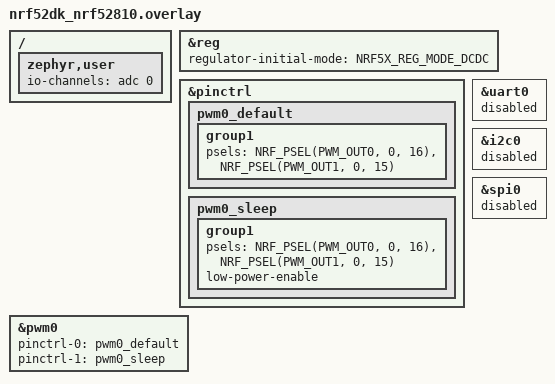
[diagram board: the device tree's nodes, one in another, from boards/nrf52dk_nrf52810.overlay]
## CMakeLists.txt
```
cmake_minimum_required(VERSION 3.20.0)
find_package(Zephyr REQUIRED HINTS $ENV{ZEPHYR_BASE})

project(nRF52810)

set(YUITAG_CORE_DIR ${CMAKE_CURRENT_SOURCE_DIR}/../../YuiTagCore)

target_include_directories(app PRIVATE
    ${CMAKE_CURRENT_SOURCE_DIR}/src
    ${YUITAG_CORE_DIR}/include
    ${YUITAG_CORE_DIR}/lib
)

target_sources(app PRIVATE
    src/main.c
    src/app.c
    src/yuitag_platform.c
    src/yuitag_buzzer.c
    src/yuitag_ble.c
    src/yuitag_findmy.c
    ${YUITAG_CORE_DIR}/src/yuitag_device.c
    ${YUITAG_CORE_DIR}/src/yuitag_crypto_common.c
    ${YUITAG_CORE_DIR}/src/yuitag_adv.c
    ${YUITAG_CORE_DIR}/src/yuitag_beep.c
    ${YUITAG_CORE_DIR}/lib/tiny_aes.c
    ${YUITAG_CORE_DIR}/lib/sha256.c
)

target_compile_definitions(app PRIVATE IS_SPARKS)
```

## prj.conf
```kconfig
# ============================================================
# YuiTag nRF52810 精简版项目编译配置
# 特性: 支持固定公钥组 FindMy / 裁剪 ECDH 软计算 / 裁剪 OTA / 裁剪 RTT 日志 / 无 MCUboot
# ============================================================

# --- 系统内核与时钟 ---
CONFIG_SYS_CLOCK_TICKS_PER_SEC=1000
CONFIG_MAIN_STACK_SIZE=1536
CONFIG_HEAP_MEM_POOL_SIZE=1024
CONFIG_SYSTEM_WORKQUEUE_STACK_SIZE=1024
CONFIG_ISR_STACK_SIZE=1024
CONFIG_PM_DEVICE=y

# --- 蓝牙协议栈 (从机从设备模式) ---
CONFIG_BT=y
CONFIG_BT_PERIPHERAL=y
CONFIG_BT_RX_STACK_SIZE=1280
CONFIG_BT_HCI_TX_STACK_SIZE=768
CONFIG_BT_DEVICE_NAME_DYNAMIC=y
CONFIG_BT_DEVICE_NAME_MAX=24
CONFIG_BT_MAX_CONN=1
CONFIG_BT_EXT_ADV=y
CONFIG_BT_EXT_ADV_MAX_ADV_SET=2
CONFIG_BT_ID_MAX=2
CONFIG_BT_BUF_ACL_RX_SIZE=64
CONFIG_BT_BUF_ACL_TX_SIZE=64
CONFIG_BT_L2CAP_TX_MTU=64
CONFIG_BT_ATT_PREPARE_COUNT=1
CONFIG_BT_BUF_EVT_RX_COUNT=6
CONFIG_BT_ASSERT=n

# 优选连接参数 (由应用层 yuitag_ble_try_conn_param_update 延迟 15 秒温和更新，禁用协议栈自动无条件降速)
CONFIG_BT_GAP_AUTO_UPDATE_CONN_PARAMS=n
CONFIG_BT_PERIPHERAL_PREF_MIN_INT=48
CONFIG_BT_PERIPHERAL_PREF_MAX_INT=72
CONFIG_BT_PERIPHERAL_PREF_LATENCY=0
CONFIG_BT_PERIPHERAL_PREF_TIMEOUT=400

# --- 硬件真随机数熵源 (用于配对密钥生成) ---
CONFIG_ENTROPY_GENERATOR=y
CONFIG_ENTROPY_NRF5_RNG=y

# --- NVS 持久化存储 ---
CONFIG_NVS=y
CONFIG_NVS_LOOKUP_CACHE=y
CONFIG_FLASH=y
CONFIG_FLASH_MAP=y
CONFIG_FLASH_PAGE_LAYOUT=y
CONFIG_MPU_ALLOW_FLASH_WRITE=y

# --- PWM 驱动 (压电蜂鸣器) ---
CONFIG_PWM=y

# --- SAADC 驱动 (电源轨 VDD 电池电量采集) ---
CONFIG_ADC=y

# --- 禁用控制台与 RTT 串口日志 (极度优化待机功耗与固件体积) ---
CONFIG_CONSOLE=n
CONFIG_USE_SEGGER_RTT=n
CONFIG_RTT_CONSOLE=n
CONFIG_UART_CONSOLE=n

# --- 射频发射功率 (最大 +4 dBm，保证最佳通信距离) ---
CONFIG_BT_CTLR_TX_PWR_ANTENNA=4
CONFIG_BT_HCI_VS=y
CONFIG_BT_CTLR_TX_PWR_DYNAMIC_CONTROL=y
```

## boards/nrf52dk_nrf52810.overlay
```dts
/*
 * YuiTag nRF52810 板级设备树 Overlay 配置:
 * 1. PWM0 驱动压电蜂鸣器差分互补输出: P0.16 (OUT0 正向, BUZZER+) / P0.15 (OUT1 反向, BUZZER-)。
 * 2. SAADC 通道 0 采样内部 VDD 电源轨，用于电池电量预估。
 * 3. 启用 SoC 内部 DC/DC 转换器降低运行功耗。
 * 4. 禁用未使用的 UART0 / I2C0 / SPI0 外设以节省静态电流。
 */

#include <zephyr/dt-bindings/regulator/nrf5x.h>

/ {
	zephyr,user {
		io-channels = <&adc 0>;
	};
};

/* 启用 SoC 内部 DC/DC 降压转换器 */
&reg {
	regulator-initial-mode = <NRF5X_REG_MODE_DCDC>;
};

&pinctrl {
	pwm0_default: pwm0_default {
		group1 {
			psels = <NRF_PSEL(PWM_OUT0, 0, 16)>,
				<NRF_PSEL(PWM_OUT1, 0, 15)>;
		};
	};

	pwm0_sleep: pwm0_sleep {
		group1 {
			psels = <NRF_PSEL(PWM_OUT0, 0, 16)>,
				<NRF_PSEL(PWM_OUT1, 0, 15)>;
			low-power-enable;
		};
	};
};

&pwm0 {
	status = "okay";
	pinctrl-0 = <&pwm0_default>;
	pinctrl-1 = <&pwm0_sleep>;
	pinctrl-names = "default", "sleep";
};

&uart0 {
	status = "disabled";
};

&i2c0 {
	status = "disabled";
};

&spi0 {
	status = "disabled";
};
```

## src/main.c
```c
// ============================================================
// YuiTag 固件程序入口与启动时序
// 硬件平台: Nordic nRF52810 / nRF Connect SDK (Zephyr)
// ============================================================

#include <zephyr/kernel.h>
#include <zephyr/bluetooth/bluetooth.h>

#include "yuitag_config.h"
#include "yuitag_platform.h"
#include "yuitag_crypto.h"
#include "yuitag_device.h"
#include "yuitag_buzzer_types.h"
#include "yuitag_ble.h"
#include "yuitag_findmy.h"
#include "app.h"

static YuiTagDevice g_dev;

// 蓝牙协议栈异步初始化就绪回调
static void bt_ready(int err)
{
    if (err) {
        platform_log("[BT] enable failed: %d", err);
        return;
    }

    platform_log("[BT] Ready");

    // 1. 获取芯片硬件 MAC 地址并初始化设备状态机与配置
    uint8_t mac[6];
    platform_get_mac(mac);
    yuitag_device_init(&g_dev, mac);

    // 2. 检测短时连续快速上电 (防抖窗口内达 5 次触发恢复出厂)
    bool resetTriggered = yuitag_device_power_cycle_check(&g_dev);

    // 3. 正常开机蜂鸣提示音 (若触发出厂复位则跳过，避免覆盖复位提示音)
    if (!resetTriggered) {
        yuitag_beep_startup();
    }

    // 4. 同步设备名称至 BLE 协议栈及 DIS 信息服务
    yuitag_ble_set_device_name(g_dev.deviceName);
    yuitag_ble_update_dis_values(&g_dev);
    yuitag_ble_update_param_value(&g_dev);

    // 5. 启动 BLE 广播 (未绑定时慢广播，已绑定时常态广播)
    yuitag_ble_update_advertising(&g_dev, true);

    // 6. 初始化 Find My 模块并在使能时启动轮换广播
    yuitag_findmy_init();
    yuitag_ble_update_param_value(&g_dev);
    if (g_dev.findmyEnabled) {
        if (!yuitag_findmy_enable()) {
            g_dev.findmyEnabled = false;
            platform_log("[FINDMY] Enable failed at boot, reverting flag");
            yuitag_ble_update_param_value(&g_dev);
        } else {
            yuitag_findmy_update_battery(g_dev.batteryLevel);
        }
    }

    // 7. 标记系统初始化完成，使能异步工作队列事件调度
    app_mark_initialized();
    platform_log("[BOOT] YuiTag initialized");
}

int main(void)
{
    // 基础硬件平台与外设初始化 (NVS 存储挂载、PWM 蜂鸣器引脚)
    platform_init();

    // 软件加密工具层初始化
    yuitag_crypto_init();

    // 异步工作队列调度器与定时器初始化
    app_init(&g_dev);

    // 注册 BLE 协议栈连接与 GATT 回调
    yuitag_ble_init(&g_dev);

    // 异步启动 Zephyr 蓝牙协议栈
    int err = bt_enable(bt_ready);
    if (err) {
        platform_log("[BT] bt_enable failed: %d", err);
    }

    // 主线程永久休眠，完全由中断与系统工作队列驱动，达到最大程度低功耗
    while (1) {
        k_sleep(K_FOREVER);
    }
    return 0;
}
```

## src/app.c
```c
// ============================================================
// YuiTag 业务事件调度中枢 (工作队列异步处理)
// 设计目的: 将耗时的 Flash 擦写 (NVS)、广播重启等操作移出蓝牙回调
//          与中断上下文，统一在 Zephyr 系统工作队列 (System Workqueue) 中安全消费。
// ============================================================

#include "app.h"
#include "yuitag_platform.h"
#include "yuitag_ble.h"

#include <zephyr/kernel.h>

static YuiTagDevice *g_dev;
static bool g_initialized = false;

static struct k_work s_process_work;
static struct k_timer s_periodic_timer;

static void process_action_handler(struct k_work *work);

// 核心业务异步消费处理函数 (调用 YuiTagCore 统一事件处理中枢)
static void process_action_handler(struct k_work *work)
{
    (void)work;
    if (!g_initialized || !g_dev) {
        return;
    }

    yuitag_device_process_events(g_dev);
}

// 系统周期定时器中断回调 (定期向工作队列提交消费任务)
static void periodic_timer_handler(struct k_timer *timer)
{
    (void)timer;
    app_proceed();
}

void app_init(YuiTagDevice *dev)
{
    g_dev = dev;

    k_work_init(&s_process_work, process_action_handler);
    k_timer_init(&s_periodic_timer, periodic_timer_handler, NULL);
    k_timer_start(&s_periodic_timer,
                  K_SECONDS(PERIODIC_CHECK_INTERVAL_MS / 1000),
                  K_SECONDS(PERIODIC_CHECK_INTERVAL_MS / 1000));
}

void app_proceed(void)
{
    k_work_submit(&s_process_work);
}

void app_mark_initialized(void)
{
    g_initialized = true;
    app_proceed();
}
```

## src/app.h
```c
#ifndef APP_H
#define APP_H

// ============================================================
// YuiTag 业务事件调度中枢 (工作队列异步处理)
// ============================================================

#include "yuitag_device.h"

// 初始化应用调度器 (绑定工作项与定时器)
void app_init(YuiTagDevice *dev);

// 提交工作队列项，触发异步事件消费处理
void app_proceed(void);

// 标记系统启动初始化完毕，使能事件消费
void app_mark_initialized(void);

#endif // APP_H
```

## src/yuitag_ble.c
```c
// ============================================================
// YuiTag BLE 协议栈与 GATT 通信层实现
// ============================================================

#include "yuitag_ble.h"
#include "yuitag_crypto.h"
#include "yuitag_platform.h"
#include "yuitag_adv.h"
#include "app.h"

#include <zephyr/bluetooth/bluetooth.h>
#include <zephyr/bluetooth/gatt.h>
#include <zephyr/bluetooth/uuid.h>
#include <zephyr/bluetooth/conn.h>
#include <zephyr/sys/byteorder.h>
#include <zephyr/sys/util.h>
#include <zephyr/kernel.h>

#include <string.h>

// 128 位完整 UUID 声明
#define YUITAG_UUID_SVC   BT_UUID_DECLARE_128(BT_UUID_128_ENCODE(0x722aaa00, 0x8a74, 0x432f, 0x9055, 0x7ed8a5584a11))
#define YUITAG_UUID_BIND  BT_UUID_DECLARE_128(BT_UUID_128_ENCODE(0x722aaa42, 0x8a74, 0x432f, 0x9055, 0x7ed8a5584a11))
#define YUITAG_UUID_CMD   BT_UUID_DECLARE_128(BT_UUID_128_ENCODE(0x722aaa43, 0x8a74, 0x432f, 0x9055, 0x7ed8a5584a11))
#define YUITAG_UUID_PARAM BT_UUID_DECLARE_128(BT_UUID_128_ENCODE(0x722aaa46, 0x8a74, 0x432f, 0x9055, 0x7ed8a5584a11))

static YuiTagDevice *g_dev;
static struct bt_conn *g_conn;
static bool g_connected = false;
static bool g_cccd_bind = false;
static bool g_cccd_cmd  = false;
static bool g_cccd_param = false;
static bool g_adv_failed = false;

static uint32_t g_conn_start_ms = 0;
static bool g_conn_param_updated = false;
static struct k_work_delayable s_conn_param_work;
static void conn_param_work_handler(struct k_work *work);

static struct k_work_delayable s_adv_refresh_work;
static void adv_refresh_work_handler(struct k_work *work)
{
    (void)work;
    if (g_dev) {
        yuitag_ble_update_advertising(g_dev, true);
        app_proceed();
    }
}

// CCCD 客户端通知特性描述符状态监听
static void ccc_bind_changed(const struct bt_gatt_attr *attr, uint16_t value)
{
    (void)attr;
    g_cccd_bind = (value == BT_GATT_CCC_NOTIFY);
    platform_log("[GATT] CCC bind notif=%d", g_cccd_bind);
}

static void ccc_cmd_changed(const struct bt_gatt_attr *attr, uint16_t value)
{
    (void)attr;
    g_cccd_cmd = (value == BT_GATT_CCC_NOTIFY);
    platform_log("[GATT] CCC cmd notif=%d", g_cccd_cmd);
}

static void ccc_param_changed(const struct bt_gatt_attr *attr, uint16_t value)
{
    (void)attr;
    g_cccd_param = (value == BT_GATT_CCC_NOTIFY);
    platform_log("[GATT] CCC param notif=%d", g_cccd_param);
}

// 根据特征 UUID 向客户端发送 GATT Notify 通知
static void notify_by_uuid(const struct bt_uuid *uuid,
                           const uint8_t *data, size_t len)
{
    if (!g_conn) {
        return;
    }

    bool ccc_enabled;
    if (!bt_uuid_cmp(uuid, YUITAG_UUID_BIND)) {
        ccc_enabled = g_cccd_bind;
    } else if (!bt_uuid_cmp(uuid, YUITAG_UUID_CMD)) {
        ccc_enabled = g_cccd_cmd;
    } else if (!bt_uuid_cmp(uuid, YUITAG_UUID_PARAM)) {
        ccc_enabled = g_cccd_param;
    } else {
        return;
    }

    if (!ccc_enabled) {
        return;
    }

    uint16_t mtu = bt_gatt_get_mtu(g_conn);
    if (len > (size_t)(mtu - 3)) {
        return;
    }

    struct bt_gatt_notify_params params = {
        .uuid = uuid,
        .attr = NULL,
        .data = data,
        .len = (uint16_t)len,
        .func = NULL,
        .user_data = NULL,
    };
    bt_gatt_notify_cb(g_conn, &params);
}

// 根据通道向客户端发送 GATT Notify 通知
static void send_notify_by_ch(yuitag_notify_ch_t ch, const uint8_t *data, size_t len)
{
    switch (ch) {
    case YUITAG_NOTIFY_BIND:
        notify_by_uuid(YUITAG_UUID_BIND, data, len);
        break;
    case YUITAG_NOTIFY_CMD:
        notify_by_uuid(YUITAG_UUID_CMD, data, len);
        break;
    case YUITAG_NOTIFY_PARAM:
        notify_by_uuid(YUITAG_UUID_PARAM, data, len);
        break;
    default:
        break;
    }
}

// 设备信息服务 (DIS) 静态字符串读取
static ssize_t read_dis_string(struct bt_conn *conn,
                               const struct bt_gatt_attr *attr,
                               void *buf, uint16_t len, uint16_t offset)
{
    const char *str = (const char *)attr->user_data;
    return bt_gatt_attr_read(conn, attr, buf, len, offset, str, strlen(str));
}

// 参数通道读取回调 (读取当前名称、广播间隔与状态)
static ssize_t read_param(struct bt_conn *conn,
                          const struct bt_gatt_attr *attr,
                          void *buf, uint16_t len, uint16_t offset)
{
    uint8_t paramBuf[PARAM_DECRYPT_BUF_MAX_LEN];
    size_t paramLen = yuitag_device_param_read(g_dev, paramBuf, sizeof(paramBuf));
    if (paramLen == 0) {
        return BT_GATT_ERR(BT_ATT_ERR_UNLIKELY);
    }
    return bt_gatt_attr_read(conn, attr, buf, len, offset, paramBuf, paramLen);
}

// 绑定特征写入回调 (触发设备端生成随机 AES 密钥并通过 Notify 发送给客户端)
static ssize_t write_bind(struct bt_conn *conn, const struct bt_gatt_attr *attr,
                          const void *buf, uint16_t len, uint16_t offset, uint8_t flags)
{
    (void)conn; (void)attr; (void)offset; (void)flags; (void)buf; (void)len;

    if (g_dev->isBound) {
        platform_log("[BIND] Ignored: already bound");
        return len;
    }

    if (g_dev->waitingVerify) {
        platform_log("[BIND] Ignored: bind already in progress");
        return len;
    }

    uint8_t aesKey[AES_KEY_LEN];
    if (!yuitag_device_bind_generate_key(g_dev, aesKey)) {
        uint8_t fail = STATUS_FAILED;
        notify_by_uuid(YUITAG_UUID_BIND, &fail, 1);
        g_dev->pendingBindAbort = true;
        app_proceed();
        return len;
    }

    notify_by_uuid(YUITAG_UUID_BIND, aesKey, AES_KEY_LEN);
    platform_log("[BIND] Sent AES key (%d bytes)", AES_KEY_LEN);
    return len;
}

// 指令通道写入回调 (处理绑定验证包及各类加密业务指令)
static ssize_t write_cmd(struct bt_conn *conn, const struct bt_gatt_attr *attr,
                         const void *buf, uint16_t len, uint16_t offset, uint8_t flags)
{
    (void)conn; (void)attr; (void)offset; (void)flags;

    yuitag_response_t resp = {0};
    yuitag_device_handle_cmd_write(g_dev, buf, len, &resp);

    if (resp.channel != YUITAG_NOTIFY_NONE) {
        send_notify_by_ch(resp.channel, resp.data, resp.len);
    }

    if (g_dev->pendingConnParamReset) {
        g_dev->pendingConnParamReset = false;
        yuitag_ble_update_dis_values(g_dev);
        g_conn_param_updated = false;
        k_work_reschedule(&s_conn_param_work, K_MSEC(CONN_PARAM_DELAY_MS));
    }

    if (g_dev->pendingUnbindClear || g_dev->pendingAdvRefresh || g_dev->pendingBindAbort) {
        app_proceed();
    }

    return len;
}

// 参数通道写入回调 (处理加密的设备名称与广播间隔修改)
static ssize_t write_param(struct bt_conn *conn, const struct bt_gatt_attr *attr,
                           const void *buf, uint16_t len, uint16_t offset, uint8_t flags)
{
    (void)conn; (void)attr; (void)offset; (void)flags;

    yuitag_response_t resp = {0};
    yuitag_device_handle_param_write(g_dev, buf, len, &resp);

    if (resp.channel != YUITAG_NOTIFY_NONE) {
        send_notify_by_ch(resp.channel, resp.data, resp.len);
    }

    if (g_dev->pendingParamSave || g_dev->pendingAdvRefresh) {
        app_proceed();
    }
    yuitag_ble_update_param_value(g_dev);

    return len;
}

static ssize_t read_serial(struct bt_conn *conn,
                           const struct bt_gatt_attr *attr,
                           void *buf, uint16_t len, uint16_t offset);

static ssize_t read_system_id(struct bt_conn *conn,
                              const struct bt_gatt_attr *attr,
                              void *buf, uint16_t len, uint16_t offset);

// ============================================================
// GATT 服务结构定义
// ============================================================

// 标准设备信息服务 (DIS: 0x180A)
BT_GATT_SERVICE_DEFINE(dis_svc,
    BT_GATT_PRIMARY_SERVICE(BT_UUID_DIS),
    BT_GATT_CHARACTERISTIC(BT_UUID_DECLARE_16(0x2A29),
        BT_GATT_CHRC_READ, BT_GATT_PERM_READ, read_dis_string, NULL, (void *)MANUFACTURER),
    BT_GATT_CHARACTERISTIC(BT_UUID_DECLARE_16(0x2A24),
        BT_GATT_CHRC_READ, BT_GATT_PERM_READ, read_dis_string, NULL, (void *)MODEL_NUMBER),
    BT_GATT_CHARACTERISTIC(BT_UUID_DECLARE_16(0x2A25),
        BT_GATT_CHRC_READ, BT_GATT_PERM_READ, read_serial, NULL, NULL),
    BT_GATT_CHARACTERISTIC(BT_UUID_DECLARE_16(0x2A23),
        BT_GATT_CHRC_READ, BT_GATT_PERM_READ, read_system_id, NULL, NULL),
    BT_GATT_CHARACTERISTIC(BT_UUID_DECLARE_16(0x2A27),
        BT_GATT_CHRC_READ, BT_GATT_PERM_READ, read_dis_string, NULL, (void *)HW_VERSION),
    BT_GATT_CHARACTERISTIC(BT_UUID_DECLARE_16(0x2A26),
        BT_GATT_CHRC_READ, BT_GATT_PERM_READ, read_dis_string, NULL, (void *)FW_VERSION),
    BT_GATT_CHARACTERISTIC(BT_UUID_DECLARE_16(0x2A28),
        BT_GATT_CHRC_READ, BT_GATT_PERM_READ, read_dis_string, NULL, (void *)YUITAG_CORE_VERSION),
);

// YuiTag 核心服务 (Core Service: 0xAA00)
BT_GATT_SERVICE_DEFINE(yuitag_core_svc,
    BT_GATT_PRIMARY_SERVICE(YUITAG_UUID_SVC),

    // 绑定握手特征 (0xAA42)
    BT_GATT_CHARACTERISTIC(YUITAG_UUID_BIND,
        BT_GATT_CHRC_WRITE | BT_GATT_CHRC_NOTIFY,
        BT_GATT_PERM_WRITE, NULL, write_bind, NULL),
    BT_GATT_CCC(ccc_bind_changed, BT_GATT_PERM_READ | BT_GATT_PERM_WRITE),

    // 控制指令通道特征 (0xAA43)
    BT_GATT_CHARACTERISTIC(YUITAG_UUID_CMD,
        BT_GATT_CHRC_WRITE | BT_GATT_CHRC_NOTIFY,
        BT_GATT_PERM_WRITE, NULL, write_cmd, NULL),
    BT_GATT_CCC(ccc_cmd_changed, BT_GATT_PERM_READ | BT_GATT_PERM_WRITE),

    // 参数配置通道特征 (0xAA46)
    BT_GATT_CHARACTERISTIC(YUITAG_UUID_PARAM,
        BT_GATT_CHRC_READ | BT_GATT_CHRC_WRITE | BT_GATT_CHRC_NOTIFY,
        BT_GATT_PERM_READ | BT_GATT_PERM_WRITE, read_param, write_param, NULL),
    BT_GATT_CCC(ccc_param_changed, BT_GATT_PERM_READ | BT_GATT_PERM_WRITE),
);

// 读取序列号特征
static ssize_t read_serial(struct bt_conn *conn,
                           const struct bt_gatt_attr *attr,
                           void *buf, uint16_t len, uint16_t offset)
{
    if (!g_dev) {
        return BT_GATT_ERR(BT_ATT_ERR_UNLIKELY);
    }
    return bt_gatt_attr_read(conn, attr, buf, len, offset,
                             g_dev->serial, strlen(g_dev->serial));
}

// 读取系统 ID 特征 (由 MAC 转换为 EUI-64 格式, 构造逻辑在 YuiTagCore)
static ssize_t read_system_id(struct bt_conn *conn,
                              const struct bt_gatt_attr *attr,
                              void *buf, uint16_t len, uint16_t offset)
{
    uint8_t mac[6];
    uint8_t sid[8];

    platform_get_mac(mac);
    yuitag_crypto_make_system_id(mac, sid);

    return bt_gatt_attr_read(conn, attr, buf, len, offset, sid, sizeof(sid));
}

#include <zephyr/bluetooth/hci.h>
#if defined(CONFIG_BT_HCI_VS) || defined(CONFIG_BT_CTLR) || defined(CONFIG_BT_LL_SOFTDEVICE)
#include <zephyr/bluetooth/hci_vs.h>
#endif

static void set_adv_tx_power(int8_t power_dbm)
{
    int8_t valid_powers[] = { 4, 3, 0, -4, -8, -12, -16, -20, -40 };
    int8_t selected = -40;
    for (size_t i = 0; i < ARRAY_SIZE(valid_powers); i++) {
        if (power_dbm >= valid_powers[i]) {
            selected = valid_powers[i];
            break;
        }
    }

#if defined(BT_HCI_OP_VS_WRITE_TX_POWER_LEVEL)
    struct bt_hci_cp_vs_write_tx_power_level *cp;
    struct net_buf *buf, *rsp = NULL;

    buf = bt_hci_cmd_alloc(K_FOREVER);
    if (buf) {
        cp = net_buf_add(buf, sizeof(*cp));
        cp->handle_type = BT_HCI_VS_LL_HANDLE_TYPE_ADV;
        cp->handle = sys_cpu_to_le16(0);
        cp->tx_power_level = selected;

        int err = bt_hci_cmd_send_sync(BT_HCI_OP_VS_WRITE_TX_POWER_LEVEL, buf, &rsp);
        if (err) {
            platform_log("[ADV] Set TX power (%d dBm) failed: %d", selected, err);
        } else {
            int8_t actual = selected;
            if (rsp && rsp->len >= sizeof(struct bt_hci_rp_vs_write_tx_power_level)) {
                struct bt_hci_rp_vs_write_tx_power_level *rp = (void *)rsp->data;
                actual = rp->selected_tx_power;
            }
            platform_log("[ADV] Set TX power: %d dBm (actual: %d dBm)", selected, actual);
        }
        if (rsp) {
            net_buf_unref(rsp);
        }
    }
#else
    ARG_UNUSED(selected);
#endif
}

// 组装广播包与扫描响应包并启动广播 (字段布局由 YuiTagCore yuitag_adv 统一构造)
static void start_advertising(YuiTagDevice *dev, bool connectable)
{
    // 主广播包字段段 (flags + 厂商数据 + [绑定后]电量 + [debug]诊断)
    uint8_t adStorage[32];
    yuitag_adv_seg_t adSegs[4];
    size_t adSegCount = yuitag_adv_build(dev, adSegs, ARRAY_SIZE(adSegs),
                                         adStorage, sizeof(adStorage));
    if (adSegCount == 0) {
        platform_log("[ADV] Failed to build adv data");
        g_adv_failed = true;
        return;
    }

    struct bt_data ad[4];
    size_t adLen = 0;
    for (size_t i = 0; i < adSegCount && adLen < ARRAY_SIZE(ad); i++) {
        ad[adLen].type = adSegs[i].type;
        ad[adLen].data_len = adSegs[i].len;
        ad[adLen].data = adSegs[i].data;
        adLen++;
    }

    // 扫描响应包中包含完整设备名称
    uint8_t sdStorage[DEVICE_NAME_MAX_LEN + 1];
    yuitag_adv_seg_t sdSegs[1];
    size_t sdSegCount = yuitag_adv_build_scan_rsp(dev, sdSegs, ARRAY_SIZE(sdSegs),
                                                  sdStorage, sizeof(sdStorage));

    struct bt_data sd[1];
    size_t sdLen = 0;
    if (sdSegCount == 1) {
        sd[0].type = sdSegs[0].type;
        sd[0].data_len = sdSegs[0].len;
        sd[0].data = sdSegs[0].data;
        sdLen = 1;
    }

    // 毫秒折算为 0.625ms 广播单位
    uint32_t units = ((uint32_t)dev->advInterval * 8U) / 5U;
    uint32_t opt = BT_LE_ADV_OPT_USE_IDENTITY;
    opt |= connectable ? BT_LE_ADV_OPT_CONN : BT_LE_ADV_OPT_SCANNABLE;
    struct bt_le_adv_param param = BT_LE_ADV_PARAM_INIT(opt, units, units, NULL);

    int err = bt_le_adv_start(&param, ad, adLen, sd, sdLen);
    if (err) {
        platform_log("[ADV] Start failed: %d", err);
        g_adv_failed = true;
        return;
    }

    set_adv_tx_power(dev->txPower);

    g_adv_failed = false;
    platform_log("[ADV] Mode=%s connectable=%d interval=%dms txPower=%d",
                 dev->isBound ? "Normal" : "Initial", connectable, dev->advInterval, dev->txPower);
}

void yuitag_ble_update_advertising(YuiTagDevice *dev, bool rebuild_data)
{
    (void)rebuild_data;
    bt_le_adv_stop();
    start_advertising(dev, !g_connected);
}

bool yuitag_ble_adv_failed(void)
{
    return g_adv_failed;
}

void yuitag_ble_disconnect(void)
{
    if (g_conn) {
        bt_conn_disconnect(g_conn, BT_HCI_ERR_REMOTE_USER_TERM_CONN);
    }
}

bool yuitag_ble_is_connected(void)
{
    return g_connected;
}

void yuitag_ble_update_param_value(YuiTagDevice *dev)
{
    (void)dev;
}

void yuitag_ble_update_dis_values(YuiTagDevice *dev)
{
    bt_set_name(dev->deviceName);
}

void yuitag_ble_set_device_name(const char *name)
{
    bt_set_name(name);
}

// 蓝牙连接建立回调
static void connected(struct bt_conn *conn, uint8_t err)
{
    if (err) {
        platform_log("[CONN] Connect failed: %u", err);
        return;
    }

    g_conn = bt_conn_ref(conn);
    g_connected = true;
    g_conn_start_ms = platform_millis();
    g_conn_param_updated = false;
    g_cccd_bind = g_cccd_cmd = g_cccd_param = false;

    yuitag_device_on_connected(g_dev);

    // 已绑定设备在连接建立 15.0 秒后尝试温和更新连接参数 (预留充裕窗口给服务发现与交互)
    if (g_dev && g_dev->isBound) {
        k_work_reschedule(&s_conn_param_work, K_MSEC(CONN_PARAM_DELAY_MS));
    }

    // 连接建立后延迟 30ms 重新配置不可连接广播，避开 BT_RX 协议栈清理竞态
    k_work_reschedule(&s_adv_refresh_work, K_MSEC(30));

    platform_log("[CONN] Connected");
}

// 蓝牙连接断开回调
static void disconnected(struct bt_conn *conn, uint8_t reason)
{
    (void)reason;
    k_work_cancel_delayable(&s_conn_param_work);

    if (g_conn) {
        bt_conn_unref(g_conn);
        g_conn = NULL;
    }
    g_connected = false;
    g_cccd_bind = g_cccd_cmd = g_cccd_param = false;

    yuitag_device_on_disconnected(g_dev);
    app_proceed();

    // 连接断开后延迟 30ms 恢复常态可连接广播，避开 BT_RX 协议栈清理竞态
    k_work_reschedule(&s_adv_refresh_work, K_MSEC(30));
    platform_log("[CONN] Disconnected (reason 0x%02x)", reason);
}

BT_CONN_CB_DEFINE(conn_callbacks) = {
    .connected = connected,
    .disconnected = disconnected,
};

static void conn_param_work_handler(struct k_work *work)
{
    (void)work;
    if (yuitag_device_is_keys_sync_active()) {
        platform_log("[CONN] Keys sync in progress, postpone conn param update");
        k_work_reschedule(&s_conn_param_work, K_SECONDS(5));
        return;
    }
    if (g_dev) {
        yuitag_ble_try_conn_param_update(g_dev);
    }
}

// 平衡功耗与响应的温和降速参数 (60ms~90ms, latency=0, timeout=4s)
void yuitag_ble_try_conn_param_update(YuiTagDevice *dev)
{
    if (!g_connected || g_conn_param_updated || !g_conn) {
        return;
    }
    if (!dev || !dev->isBound) {
        return;
    }
    if (platform_millis() - g_conn_start_ms < CONN_PARAM_DELAY_MS) {
        return;
    }
    if (yuitag_device_is_keys_sync_active()) {
        platform_log("[CONN] Keys sync in progress, postpone conn param update");
        k_work_reschedule(&s_conn_param_work, K_SECONDS(5));
        return;
    }

    struct bt_le_conn_param param = {
        .interval_min = CONN_PARAM_INTERVAL_MIN_UNITS,
        .interval_max = CONN_PARAM_INTERVAL_MAX_UNITS,
        .latency = CONN_PARAM_LATENCY,
        .timeout = CONN_PARAM_TIMEOUT_UNITS,
    };
    int err = bt_conn_le_param_update(g_conn, &param);
    if (err == 0) {
        g_conn_param_updated = true;
        platform_log("[CONN] Balanced param update requested: 60-90ms, lat=0, to=4s");
    } else {
        platform_log("[CONN] Param update failed: %d", err);
    }
}

void yuitag_ble_init(YuiTagDevice *dev)
{
    g_dev = dev;
    k_work_init_delayable(&s_conn_param_work, conn_param_work_handler);
    k_work_init_delayable(&s_adv_refresh_work, adv_refresh_work_handler);
}
```

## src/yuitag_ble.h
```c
#ifndef YUITAG_BLE_H
#define YUITAG_BLE_H

// ============================================================
// YuiTag BLE 协议栈与 GATT 通信层接口
// 硬件平台: Nordic nRF52810 / Zephyr Bluetooth Host
// 功能: 广播控制、GATT 核心服务与特征、连接参数协商、通知推送
// ============================================================

#include <zephyr/bluetooth/bluetooth.h>
#include "yuitag_device.h"
#include <stdbool.h>

// 初始化 BLE 驱动层上下文及连接参数更新工作项 (需在 bt_enable 前调用)
void yuitag_ble_init(YuiTagDevice *dev);

// 更新广播数据包内容并启动/重置广播
void yuitag_ble_update_advertising(YuiTagDevice *dev, bool rebuild_data);

// 主动断开当前 BLE 连接
void yuitag_ble_disconnect(void);

// 查询当前是否处于连接状态
bool yuitag_ble_is_connected(void);

// 查询广播启动是否发生错误
bool yuitag_ble_adv_failed(void);

// 触发参数特征与 DIS 服务相关值更新
void yuitag_ble_update_param_value(YuiTagDevice *dev);
void yuitag_ble_update_dis_values(YuiTagDevice *dev);
void yuitag_ble_set_device_name(const char *name);

// 尝试向主机发起连接参数更新请求 (遵循 Apple iOS 配件规范)
void yuitag_ble_try_conn_param_update(YuiTagDevice *dev);

#endif // YUITAG_BLE_H
```

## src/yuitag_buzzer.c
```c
// ============================================================
// YuiTag 蜂鸣器驱动层实现
// 硬件平台: Nordic nRF52810 / Zephyr PWM
// 驱动原理: 通道 0 与通道 1 互补差分输出 (180° 相位差)，获得倍增声压。
//          关闭时双通道均拉低至 0V，消除压电蜂鸣片直流偏置漏电。
// ============================================================

#include "yuitag_buzzer.h"

#include <zephyr/kernel.h>
#include <zephyr/device.h>
#include <zephyr/devicetree.h>
#include <zephyr/drivers/pwm.h>
#if defined(CONFIG_PM_DEVICE)
#include <zephyr/pm/device.h>
#endif
#include <hal/nrf_pwm.h>

#define BUZZER_NODE             DT_NODELABEL(pwm0)
#define BUZZER_DEV              DEVICE_DT_GET(BUZZER_NODE)
#define BUZZER_CH_P             0
#define BUZZER_CH_N             1

#define BUZZER_DEFAULT_FREQ     4000U       // 压电片共振主频 4kHz
#define BUZZER_DEFAULT_VOLUME   100U        // 默认满音量
#define BUZZER_TIMER_CLOCK_HZ   16000000U   // nRF52810 PWM 高频时钟 (16MHz)

static bool s_buzzer_on;
static uint32_t s_freq = BUZZER_DEFAULT_FREQ;
static uint8_t  s_volume_pct = BUZZER_DEFAULT_VOLUME;

static const buzzer_note_t *s_melody_notes;
static uint16_t             s_melody_count;
static uint16_t             s_melody_index;
static bool                 s_melody_repeat;
static bool                 s_melody_playing;
static buzzer_melody_done_cb s_melody_done_cb;

static struct k_work_delayable s_melody_work;

static void melody_step(struct k_work *work);
static void play_current_note(void);
static void timer_apply(void);

// 应用当前频率和音量到双路差分 PWM 输出
static void timer_apply(void)
{
    if (!device_is_ready(BUZZER_DEV)) {
        return;
    }

#if defined(CONFIG_PM_DEVICE)
    pm_device_action_run(BUZZER_DEV, PM_DEVICE_ACTION_RESUME);
#endif
    nrf_pwm_enable(NRF_PWM0);

    // 计算 PWM 周期计数值 (时钟频率 / 目标频率)
    uint32_t period = BUZZER_TIMER_CLOCK_HZ / s_freq;
    if (period < 2U) {
        period = 2U;
    }

    uint8_t vol = s_volume_pct;
    if (vol > 100U) {
        vol = 100U;
    }

    // 满音量对应 50% 占空比 (差分驱动下可达到最大振幅)
    uint32_t pulse = (period * vol) / 200U;
    if (pulse < 1U) {
        pulse = 1U;
    }
    if (pulse >= period) {
        pulse = period - 1U;
    }

    // 通道 0 正常极性，通道 1 反向极性 (形成 180° 差分信号)
    pwm_set_cycles(BUZZER_DEV, BUZZER_CH_P, period, pulse, PWM_POLARITY_NORMAL);
    pwm_set_cycles(BUZZER_DEV, BUZZER_CH_N, period, pulse, PWM_POLARITY_INVERTED);
}

void buzzer_init(void)
{
    s_buzzer_on    = false;
    s_volume_pct   = BUZZER_DEFAULT_VOLUME;
    s_freq         = BUZZER_DEFAULT_FREQ;
    s_melody_playing = false;

    if (device_is_ready(BUZZER_DEV)) {
        pwm_set_cycles(BUZZER_DEV, BUZZER_CH_P, 0, 0, PWM_POLARITY_NORMAL);
        pwm_set_cycles(BUZZER_DEV, BUZZER_CH_N, 0, 0, PWM_POLARITY_NORMAL);
#if defined(CONFIG_PM_DEVICE)
        pm_device_action_run(BUZZER_DEV, PM_DEVICE_ACTION_SUSPEND);
#endif
        nrf_pwm_disable(NRF_PWM0);
    }

    k_work_init_delayable(&s_melody_work, melody_step);
}

void buzzer_on(void)
{
    if (s_buzzer_on) {
        return;
    }
    timer_apply();
    s_buzzer_on = true;
}

void buzzer_off(void)
{
    if (!s_buzzer_on) {
        return;
    }
    if (device_is_ready(BUZZER_DEV)) {
        // 双通道均输出 0 脉宽正常极性 (拉低至 0V)，彻底消除直流偏置与静态漏电
        pwm_set_cycles(BUZZER_DEV, BUZZER_CH_P, 0, 0, PWM_POLARITY_NORMAL);
        pwm_set_cycles(BUZZER_DEV, BUZZER_CH_N, 0, 0, PWM_POLARITY_NORMAL);

#if defined(CONFIG_PM_DEVICE)
        pm_device_action_run(BUZZER_DEV, PM_DEVICE_ACTION_SUSPEND);
#endif
        nrf_pwm_disable(NRF_PWM0);
    }
    s_buzzer_on = false;
}

bool buzzer_toggle(void)
{
    if (s_buzzer_on) {
        buzzer_off();
    } else {
        buzzer_on();
    }
    return s_buzzer_on;
}

bool buzzer_is_on(void)
{
    return s_buzzer_on;
}

void buzzer_set_volume(uint8_t volume_pct)
{
    if (volume_pct > 100U) {
        volume_pct = 100U;
    }
    s_volume_pct = volume_pct;
    if (s_buzzer_on) {
        timer_apply();
    }
}

// 播放当前索引指向的音符
static void play_current_note(void)
{
    while (s_melody_index < s_melody_count && s_melody_notes[s_melody_index].duration_ms == 0) {
        s_melody_index++;
    }

    if (s_melody_index >= s_melody_count) {
        if (s_melody_repeat && s_melody_count > 0) {
            s_melody_index = 0;
            while (s_melody_index < s_melody_count && s_melody_notes[s_melody_index].duration_ms == 0) {
                s_melody_index++;
            }
            if (s_melody_index >= s_melody_count) {
                s_melody_playing = false;
                buzzer_off();
                if (s_melody_done_cb) {
                    s_melody_done_cb(true);
                }
                return;
            }
        } else {
            s_melody_playing = false;
            buzzer_off();
            if (s_melody_done_cb) {
                s_melody_done_cb(true);
            }
            return;
        }
    }

    const buzzer_note_t *note = &s_melody_notes[s_melody_index];

    if (note->freq == 0) {
        buzzer_off(); // 休止符
    } else {
        if (note->freq != s_freq) {
            s_freq = note->freq;
            timer_apply();
        }
        if (!s_buzzer_on) {
            buzzer_on();
        }
    }

    k_work_reschedule(&s_melody_work, K_MSEC(note->duration_ms));
}

// 乐谱播放延时工作队列处理回调
static void melody_step(struct k_work *work)
{
    (void)work;
    if (!s_melody_playing) {
        return;
    }

    s_melody_index++;
    play_current_note();
}

void buzzer_play_melody(const buzzer_note_t *notes, uint16_t count,
                        bool repeat, buzzer_melody_done_cb cb)
{
    if (!notes || count == 0) {
        return;
    }
    buzzer_stop_melody();

    s_melody_notes   = notes;
    s_melody_count   = count;
    s_melody_index   = 0;
    s_melody_repeat  = repeat;
    s_melody_done_cb = cb;
    s_melody_playing = true;

    play_current_note();
}

void buzzer_stop_melody(void)
{
    if (!s_melody_playing) {
        return;
    }
    k_work_cancel_delayable(&s_melody_work);
    s_melody_playing = false;
    buzzer_off();
    if (s_melody_done_cb) {
        s_melody_done_cb(false);
    }
}

bool buzzer_melody_is_playing(void)
{
    return s_melody_playing;
}
```

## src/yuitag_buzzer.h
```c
#ifndef YUITAG_BUZZER_H
#define YUITAG_BUZZER_H

// ============================================================
// YuiTag 蜂鸣器驱动层接口
// 硬件平台: Nordic nRF52810 (Zephyr PWM 双通道互补差分驱动)
// 特性: 基于 k_work_delayable 的非阻塞异步乐谱播放引擎
// ============================================================

#include "yuitag_buzzer_types.h"

#endif // YUITAG_BUZZER_H
```

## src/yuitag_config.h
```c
#ifndef YUITAG_CONFIG_H
#define YUITAG_CONFIG_H

// ============================================================
// YuiTag Sparks (nRF52810) 平台配置
// 架构: nRF Connect SDK / Zephyr RTOS
// ============================================================

#include <stdint.h>
#include <stddef.h>
#include <stdbool.h>

// ---- 版本标识: Sparks (低配版，无 FindMy / 无 ECDH / 无 OTA) ----
#ifndef IS_SPARKS
#define IS_SPARKS
#endif

// ---- 编译期日志开关与输出宏 ----
#ifndef YUITAG_LOG_ENABLE
#define YUITAG_LOG_ENABLE           0       // 0: 关闭日志输出, 1: 开启日志输出
#endif

#if YUITAG_LOG_ENABLE
#include <zephyr/sys/printk.h>
#define platform_log(fmt, ...)  printk(fmt "\n", ##__VA_ARGS__)
#else
#define platform_log(fmt, ...)  ((void)0)
#endif

// ---- 固件与设备信息 ----
#define FW_VERSION                  "1.0.0|NCS"
#define HW_VERSION                  "V1|NRF52"
#define MANUFACTURER                "Yuitwork Labs 唯晴科技"
#define MODEL_NUMBER                "YuiTag Sparks|YLS05N"
#define DEVICE_NAME_PREFIX          "YuiTag Sparks_"

// ---- 硬件射频发射功率边界 (dBm) ----
#ifndef HW_TX_POWER_MIN
#define HW_TX_POWER_MIN             (-40)   // nRF52 硬件支持最低发射功率 (dBm)
#endif
#ifndef HW_TX_POWER_MAX
#define HW_TX_POWER_MAX             4       // nRF52810 硬件支持最高发射功率 (dBm)
#endif

// ---- 引入跨平台公共协议常量 ----
#include "yuitag_config_common.h"

#endif // YUITAG_CONFIG_H
```

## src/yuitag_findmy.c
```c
// ============================================================
// YuiTag Sparks (nRF52810) Apple Find My 模块实现
// 特性: 预置固定公钥组轮换 (5~50 个公钥)
//       无需 ECC 椭圆曲线计算，内存与 Flash 占用极低
//       使用独立 Identity 1 配合 Extended Advertising 轮转随机地址
// ============================================================

#include "yuitag_config.h"
#include "yuitag_platform_api.h"
#include "yuitag_findmy.h"
#include "yuitag_adv.h"

#include <zephyr/bluetooth/bluetooth.h>
#include <zephyr/bluetooth/addr.h>
#include <zephyr/bluetooth/hci.h>
#include <zephyr/sys/byteorder.h>
#include <zephyr/sys/util.h>

#if defined(CONFIG_BT_HCI_VS) || defined(CONFIG_BT_CTLR) || defined(CONFIG_BT_LL_SOFTDEVICE)
#include <zephyr/bluetooth/hci_vs.h>
#endif

#include <errno.h>
#include <string.h>

#define FINDMY_ID 1

static struct bt_le_ext_adv *s_adv = NULL;
static int8_t   s_findmy_tx_power = DEFAULT_FINDMY_TX_POWER;
static uint16_t s_findmy_adv_interval_ms = FINDMY_ADV_INTERVAL_DEFAULT_MS;
static bool     s_advertising = false;

static bool s_keys_load_key(uint8_t index, uint8_t key_out[FINDMY_KEY_LEN]);

static uint8_t  s_key_count = 0;
static uint8_t  s_current_idx = 0;
static uint32_t s_period_seconds = FINDMY_DEFAULT_PERIOD_SEC;
static uint32_t s_last_rotate_ms = 0;
static uint8_t  s_battery_status = 0;
static uint8_t  s_last_error = 0;

// ============================================================
// 射频发射功率控制
// ============================================================
static void set_ext_adv_tx_power(struct bt_le_ext_adv *adv, int8_t power_dbm)
{
    if (!adv) return;
    int8_t valid_powers[] = { 4, 3, 0, -4, -8, -12, -16, -20, -40 };
    int8_t selected = -40;
    for (size_t i = 0; i < ARRAY_SIZE(valid_powers); i++) {
        if (power_dbm >= valid_powers[i]) {
            selected = valid_powers[i];
            break;
        }
    }

#if defined(BT_HCI_OP_VS_WRITE_TX_POWER_LEVEL)
    struct bt_hci_cp_vs_write_tx_power_level *cp;
    struct net_buf *buf, *rsp = NULL;

    buf = bt_hci_cmd_alloc(K_FOREVER);
    if (buf) {
        cp = net_buf_add(buf, sizeof(*cp));
        cp->handle_type = BT_HCI_VS_LL_HANDLE_TYPE_ADV;
        cp->handle = sys_cpu_to_le16(bt_le_ext_adv_get_index(adv));
        cp->tx_power_level = selected;

        int err = bt_hci_cmd_send_sync(BT_HCI_OP_VS_WRITE_TX_POWER_LEVEL, buf, &rsp);
        if (err) {
            platform_log("[FINDMY] Set TX power (%d dBm, handle=%d) failed: %d",
                         selected, bt_le_ext_adv_get_index(adv), err);
        } else {
            int8_t actual = selected;
            if (rsp && rsp->len >= sizeof(struct bt_hci_rp_vs_write_tx_power_level)) {
                struct bt_hci_rp_vs_write_tx_power_level *rp = (void *)rsp->data;
                actual = rp->selected_tx_power;
            }
            platform_log("[FINDMY] Set TX power: %d dBm (actual: %d dBm, handle=%d)",
                         selected, actual, bt_le_ext_adv_get_index(adv));
        }
        if (rsp) {
            net_buf_unref(rsp);
        }
    }
#else
    ARG_UNUSED(selected);
#endif
}

void platform_findmy_adv_set_tx_power(int8_t power_dbm)
{
    s_findmy_tx_power = power_dbm;
    if (s_adv) {
        set_ext_adv_tx_power(s_adv, power_dbm);
    }
}

void platform_findmy_adv_set_interval(uint16_t interval_ms)
{
    s_findmy_adv_interval_ms = interval_ms;
    if (s_adv && s_advertising) {
        uint8_t curKey[FINDMY_KEY_LEN];
        if (s_keys_load_key(s_current_idx, curKey)) {
            platform_findmy_adv_start(curKey, s_battery_status);
        }
    }
}

// ============================================================
// BLE Identity 1 随机地址配置
// ============================================================
static bool ensure_identity(const uint8_t key[FINDMY_KEY_LEN])
{
    bt_addr_le_t addrs[CONFIG_BT_ID_MAX];
    size_t count = ARRAY_SIZE(addrs);

    bt_id_get(addrs, &count);
    if (count > FINDMY_ID) {
        return true;
    }

    bt_addr_le_t addr;
    addr.type = BT_ADDR_LE_RANDOM;
    yuitag_findmy_key_to_addr(key, addr.a.val);
    int err = bt_id_create(&addr, NULL);
    if (err < 0 && err != -EALREADY) {
        platform_log("[FINDMY] id_create failed: %d", err);
        return false;
    }
    return true;
}

// ============================================================
// 广播底层启动/更新/停止 (实现 platform_findmy_adv_*)
// ============================================================
bool platform_findmy_adv_start(const uint8_t key[28], uint8_t status_byte)
{
    int err;

    if (s_adv) {
        bt_le_ext_adv_stop(s_adv);
        bt_le_ext_adv_delete(s_adv);
        s_adv = NULL;
    }

    if (!ensure_identity(key)) {
        return false;
    }

    bt_addr_le_t addr;
    addr.type = BT_ADDR_LE_RANDOM;
    yuitag_findmy_key_to_addr(key, addr.a.val);
    err = bt_id_reset(FINDMY_ID, &addr, NULL);
    if (err < 0 && err != -EALREADY) {
        platform_log("[FINDMY] id_reset failed: %d", err);
        return false;
    }

    uint32_t units = ((uint32_t)s_findmy_adv_interval_ms * 8U) / 5U;
    uint32_t opt = BT_LE_ADV_OPT_USE_IDENTITY;
    struct bt_le_adv_param param = BT_LE_ADV_PARAM_INIT(opt, units, units, NULL);
    param.id = FINDMY_ID;

    err = bt_le_ext_adv_create(&param, NULL, &s_adv);
    if (err) {
        platform_log("[FINDMY] ext_adv_create failed: %d", err);
        return false;
    }

    set_ext_adv_tx_power(s_adv, s_findmy_tx_power);

    uint8_t raw[31];
    yuitag_findmy_build_adv_data(key, status_byte, raw);
    struct bt_data ad[] = {
        BT_DATA(BT_DATA_MANUFACTURER_DATA, &raw[2], 29),
    };

    err = bt_le_ext_adv_set_data(s_adv, ad, ARRAY_SIZE(ad), NULL, 0);
    if (err) {
        platform_log("[FINDMY] set_data failed: %d", err);
        return false;
    }

    err = bt_le_ext_adv_start(s_adv, BT_LE_EXT_ADV_START_DEFAULT);
    if (err) {
        platform_log("[FINDMY] adv start failed: %d", err);
        return false;
    }

    return true;
}

bool platform_findmy_adv_update_data(const uint8_t key[28], uint8_t status_byte)
{
    if (!s_adv) {
        return false;
    }

    uint8_t raw[31];
    yuitag_findmy_build_adv_data(key, status_byte, raw);
    struct bt_data ad[] = {
        BT_DATA(BT_DATA_MANUFACTURER_DATA, &raw[2], 29),
    };

    return (bt_le_ext_adv_set_data(s_adv, ad, ARRAY_SIZE(ad), NULL, 0) == 0);
}

void platform_findmy_adv_stop(void)
{
    if (s_adv) {
        bt_le_ext_adv_stop(s_adv);
        bt_le_ext_adv_delete(s_adv);
        s_adv = NULL;
    }
}

// ============================================================
// Sparks 固定密钥管理与周期轮换
// ============================================================
static bool s_keys_load_key(uint8_t index, uint8_t key_out[FINDMY_KEY_LEN])
{
    if (index >= s_key_count) {
        return false;
    }
    size_t loaded = platform_storage_load_bytes(NVM3_KEY_FINDMY_KEY_BASE + index, key_out, FINDMY_KEY_LEN);
    return (loaded == FINDMY_KEY_LEN);
}

bool yuitag_findmy_reload_keys(void)
{
    uint16_t count = platform_storage_load_u16(NVM3_KEY_FINDMY_KEY_COUNT, 0);
    if (count < FINDMY_MIN_KEYS || count > FINDMY_MAX_KEYS) {
        s_key_count = 0;
        platform_log("[FINDMY] No valid keys in storage (count=%d)", count);
        return false;
    }

    s_key_count = (uint8_t)count;
    uint16_t curIdx = platform_storage_load_u16(NVM3_KEY_FINDMY_CURRENT_IDX, 0);
    s_current_idx = (curIdx < s_key_count) ? (uint8_t)curIdx : 0;
    platform_log("[FINDMY] Keys ready: %d keys, current_idx=%d", s_key_count, s_current_idx);

    if (s_advertising) {
        uint8_t curKey[FINDMY_KEY_LEN];
        if (s_keys_load_key(s_current_idx, curKey)) {
            platform_findmy_adv_start(curKey, s_battery_status);
        }
    }
    return true;
}

void yuitag_findmy_init(void)
{
    s_advertising = false;
    s_last_error = 0;
    s_last_rotate_ms = platform_millis();

    uint32_t storedPeriod = 0;
    size_t loaded = platform_storage_load_bytes(NVM3_KEY_FINDMY_PERIOD_SEC,
                                                (uint8_t *)&storedPeriod, sizeof(storedPeriod));
    if (loaded == sizeof(storedPeriod) && storedPeriod >= FINDMY_PERIOD_MIN_SEC && storedPeriod <= FINDMY_PERIOD_MAX_SEC) {
        s_period_seconds = storedPeriod;
    } else {
        s_period_seconds = FINDMY_DEFAULT_PERIOD_SEC;
    }

    yuitag_findmy_reload_keys();
}

void yuitag_findmy_tick(void)
{
    if (!s_advertising || s_key_count < FINDMY_MIN_KEYS) {
        return;
    }

    uint32_t now = platform_millis();
    if ((now - s_last_rotate_ms) >= (s_period_seconds * 1000UL)) {
        s_last_rotate_ms = now;
        s_current_idx = (s_current_idx + 1) % s_key_count;

        uint8_t nextKey[FINDMY_KEY_LEN];
        if (s_keys_load_key(s_current_idx, nextKey)) {
            platform_findmy_adv_start(nextKey, s_battery_status);
            platform_log("[FINDMY] Rotated to key %d/%d", s_current_idx, s_key_count);
        } else {
            platform_log("[FINDMY] Failed to load key %d/%d", s_current_idx, s_key_count);
        }
    }
}

void yuitag_findmy_update_battery(uint8_t battery_percent)
{
    uint8_t battery_bits;
    if (battery_percent > 80) {
        battery_bits = 0x00;
    } else if (battery_percent > 50) {
        battery_bits = 0x40;
    } else if (battery_percent > 30) {
        battery_bits = 0x80;
    } else {
        battery_bits = 0xC0;
    }

    uint8_t old_battery = s_battery_status & 0xC0;
    if (old_battery == battery_bits) {
        return;
    }

    s_battery_status = battery_bits | (s_battery_status & 0x3F);
    if (s_advertising && s_key_count > 0) {
        uint8_t curKey[FINDMY_KEY_LEN];
        if (s_keys_load_key(s_current_idx, curKey)) {
            platform_findmy_adv_update_data(curKey, s_battery_status);
        }
    }
}

bool yuitag_findmy_enable(void)
{
    if (s_key_count < FINDMY_MIN_KEYS) {
        platform_log("[FINDMY] Cannot enable: keys not configured (%d)", s_key_count);
        return false;
    }

    uint8_t curKey[FINDMY_KEY_LEN];
    if (!s_keys_load_key(s_current_idx, curKey)) {
        platform_log("[FINDMY] Failed to load key %d", s_current_idx);
        return false;
    }

    if (platform_findmy_adv_start(curKey, s_battery_status)) {
        s_advertising = true;
        s_last_rotate_ms = platform_millis();
        platform_log("[FINDMY] Enabled (key %d/%d)", s_current_idx, s_key_count);
        return true;
    }
    return false;
}

void yuitag_findmy_disable(void)
{
    platform_findmy_adv_stop();
    s_advertising = false;
    platform_log("[FINDMY] Disabled");
}

bool yuitag_findmy_is_enabled(void)
{
    return s_advertising;
}

void yuitag_findmy_set_period(uint32_t seconds)
{
    if (seconds < FINDMY_PERIOD_MIN_SEC) seconds = FINDMY_PERIOD_MIN_SEC;
    if (seconds > FINDMY_PERIOD_MAX_SEC) seconds = FINDMY_PERIOD_MAX_SEC;
    if (seconds == s_period_seconds) return;

    s_period_seconds = seconds;
    platform_storage_save_bytes(NVM3_KEY_FINDMY_PERIOD_SEC,
                                (uint8_t *)&s_period_seconds, sizeof(s_period_seconds));
    s_last_rotate_ms = platform_millis();
    platform_log("[FINDMY] Period set to %lu sec", seconds);
}

uint32_t yuitag_findmy_get_period(void)
{
    return s_period_seconds;
}

uint32_t yuitag_findmy_period_index_to_seconds(uint8_t index)
{
    switch (index) {
        case 0:  return 900;
        case 1:  return 1800;
        case 2:  return 3600;
        case 3:  return 7200;
        default: return 3600;
    }
}

uint8_t yuitag_findmy_period_seconds_to_index(uint32_t seconds)
{
    if (seconds <= 900)  return 0;
    if (seconds <= 1800) return 1;
    if (seconds <= 3600) return 2;
    return 3;
}

bool yuitag_findmy_get_current_key(uint8_t keyOut[FINDMY_KEY_LEN])
{
    if (s_key_count < FINDMY_MIN_KEYS) return false;
    return s_keys_load_key(s_current_idx, keyOut);
}

uint8_t yuitag_findmy_get_status(void)
{
    uint8_t status = 0;
    if (s_advertising)                  status |= 0x01;
    if (s_key_count >= FINDMY_MIN_KEYS) status |= 0x04;
    return status;
}

uint8_t yuitag_findmy_get_last_error(void)
{
    return s_last_error;
}

void yuitag_findmy_clear_seed(void)
{
    yuitag_findmy_disable();
    for (uint8_t i = 0; i < s_key_count && i < FINDMY_MAX_KEYS; i++) {
        platform_storage_remove(NVM3_KEY_FINDMY_KEY_BASE + i);
    }
    s_key_count = 0;
    s_current_idx = 0;
    platform_storage_remove(NVM3_KEY_FINDMY_KEY_COUNT);
    platform_storage_remove(NVM3_KEY_FINDMY_CURRENT_IDX);
    platform_storage_remove(NVM3_KEY_FINDMY_KEYS_BLOB);
    platform_log("[FINDMY] Keys cleared");
}

bool yuitag_findmy_has_keys(void)
{
    return (s_key_count >= FINDMY_MIN_KEYS);
}

uint8_t yuitag_findmy_get_key_count(void)
{
    return s_key_count;
}

uint8_t yuitag_findmy_get_current_key_index(void)
{
    return s_current_idx;
}
```

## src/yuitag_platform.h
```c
#ifndef YUITAG_PLATFORM_H
#define YUITAG_PLATFORM_H

// ============================================================
// YuiTag 平台驱动层接口 - Nordic nRF52810 / Zephyr
// 遵循 YuiTagCore 的 yuitag_platform_api.h 平台契约
// ============================================================

#include "yuitag_config.h"
#include "yuitag_platform_api.h"

void platform_init(void);

#endif // YUITAG_PLATFORM_H
```
